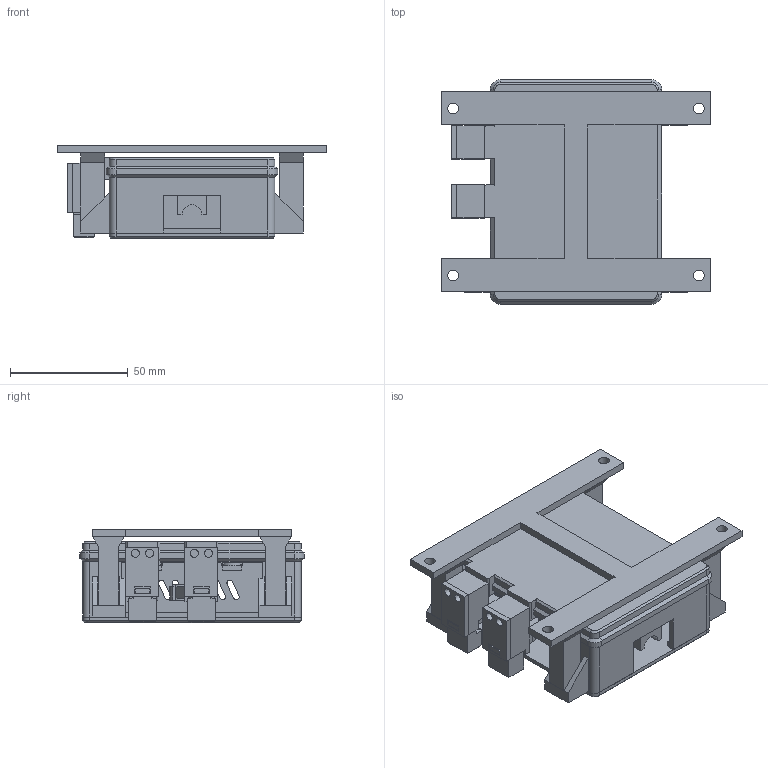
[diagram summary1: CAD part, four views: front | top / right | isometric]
STEP (ISO 10303-21) file: header records copied from the file, then geometry measured from it (millimetres).
FILE_DESCRIPTION(('Open CASCADE Model'),'2;1');
FILE_NAME('Open CASCADE Shape Model','2026-10-19T19:32:54',('Author'),( 'Open CASCADE'),'Open CASCADE STEP processor 7.9','build123d', 'Unknown');
FILE_SCHEMA(('AUTOMOTIVE_DESIGN { 1 0 10303 214 1 1 1 1 }'));
Length unit declared in the file: millimetre
Products named in the file (16): COMPOUND
Assembly tree (15 placements, depth 2):
  COMPOUND
    COMPOUND
    COMPOUND
    COMPOUND
    COMPOUND
    COMPOUND
    COMPOUND
    COMPOUND
    COMPOUND
    COMPOUND
    COMPOUND
    COMPOUND
    COMPOUND
    COMPOUND
    COMPOUND
    COMPOUND
Bounding box: 114.3 x 95.2 x 39.6 mm (x, y, z)
Volume: 94116 mm3; surface area: 74138.1 mm2
Topology: 15 solids, 15 shells, 661 faces, 1698 edges, 1107 vertices
Faces by surface type: plane 522, cylinder 123, cone 16
Full cylindrical faces by diameter (mm): 3.4 x22, 4 x12, 4.1 x6, 4.5 x4
Entity records: 41672 total; most frequent: CARTESIAN_POINT 8452, DIRECTION 5650, LINE 3636, VECTOR 3636, ORIENTED_EDGE 3396, PCURVE 3396, DEFINITIONAL_REPRESENTATION 3396, EDGE_CURVE 1698
One B-rep face of a CAD part: STEP entity #12112.
In plain terms, the planar face has unit normal (0, 1, 0).
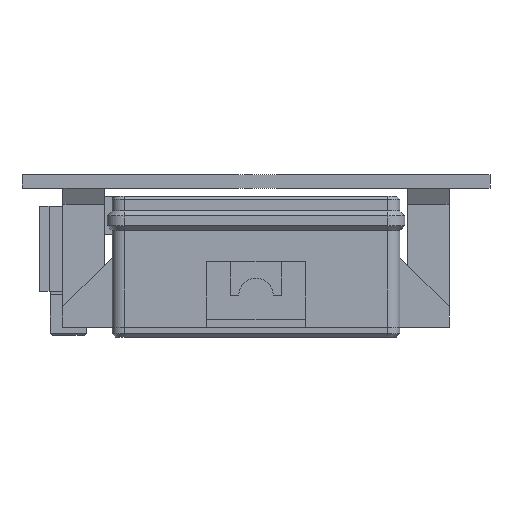
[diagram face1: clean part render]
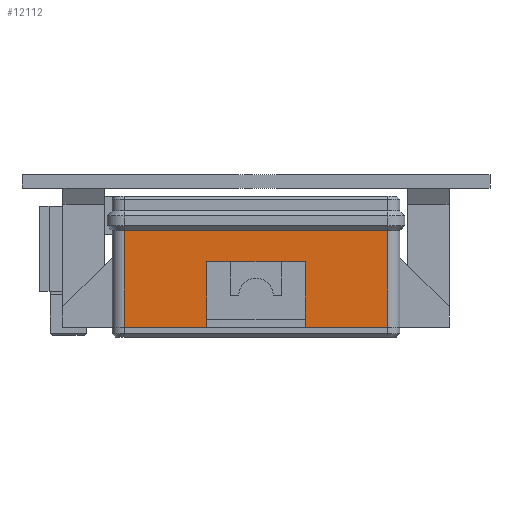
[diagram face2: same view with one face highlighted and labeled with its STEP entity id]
Its self-contained STEP definition (entity closure, numbers rounded to 3 decimals):
#2296 = PLANE('',#2297);
#2297 = AXIS2_PLACEMENT_3D('',#2298,#2299,#2300);
#2298 = CARTESIAN_POINT('',(-35.15,-46.4,32.));
#2299 = DIRECTION('',(0.,0.,1.));
#2300 = DIRECTION('',(1.,0.,-0.));
#5967 = VERTEX_POINT('',#5968);
#5968 = CARTESIAN_POINT('',(32.15,46.4,32.));
#5983 = CYLINDRICAL_SURFACE('',#5984,3.);
#5984 = AXIS2_PLACEMENT_3D('',#5985,#5986,#5987);
#5985 = CARTESIAN_POINT('',(32.15,43.4,0.));
#5986 = DIRECTION('',(0.,0.,1.));
#5987 = DIRECTION('',(1.,0.,-0.));
#5995 = EDGE_CURVE('',#5996,#5967,#5998,.T.);
#5996 = VERTEX_POINT('',#5997);
#5997 = CARTESIAN_POINT('',(12.,46.4,32.));
#5998 = SURFACE_CURVE('',#5999,(#6003,#6010),.PCURVE_S1.);
#5999 = LINE('',#6000,#6001);
#6000 = CARTESIAN_POINT('',(-35.15,46.4,32.));
#6001 = VECTOR('',#6002,1.);
#6002 = DIRECTION('',(1.,0.,-0.));
#6003 = PCURVE('',#2296,#6004);
#6004 = DEFINITIONAL_REPRESENTATION('',(#6005),#6009);
#6005 = LINE('',#6006,#6007);
#6006 = CARTESIAN_POINT('',(0.,92.8));
#6007 = VECTOR('',#6008,1.);
#6008 = DIRECTION('',(1.,0.));
#6009 = ( GEOMETRIC_REPRESENTATION_CONTEXT(2) 
PARAMETRIC_REPRESENTATION_CONTEXT() REPRESENTATION_CONTEXT('2D SPACE',''
  ) );
#6010 = PCURVE('',#6011,#6016);
#6011 = PLANE('',#6012);
#6012 = AXIS2_PLACEMENT_3D('',#6013,#6014,#6015);
#6013 = CARTESIAN_POINT('',(-35.15,46.4,0.));
#6014 = DIRECTION('',(-0.,1.,0.));
#6015 = DIRECTION('',(0.,0.,1.));
#6016 = DEFINITIONAL_REPRESENTATION('',(#6017),#6021);
#6017 = LINE('',#6018,#6019);
#6018 = CARTESIAN_POINT('',(32.,0.));
#6019 = VECTOR('',#6020,1.);
#6020 = DIRECTION('',(0.,1.));
#6021 = ( GEOMETRIC_REPRESENTATION_CONTEXT(2) 
PARAMETRIC_REPRESENTATION_CONTEXT() REPRESENTATION_CONTEXT('2D SPACE',''
  ) );
#6039 = PLANE('',#6040);
#6040 = AXIS2_PLACEMENT_3D('',#6041,#6042,#6043);
#6041 = CARTESIAN_POINT('',(12.,43.5,16.));
#6042 = DIRECTION('',(1.,0.,-0.));
#6043 = DIRECTION('',(0.,0.,1.));
#7090 = PLANE('',#7091);
#7091 = AXIS2_PLACEMENT_3D('',#7092,#7093,#7094);
#7092 = CARTESIAN_POINT('',(-35.15,-46.4,32.));
#7093 = DIRECTION('',(0.,0.,1.));
#7094 = DIRECTION('',(1.,0.,-0.));
#8327 = CYLINDRICAL_SURFACE('',#8328,3.);
#8328 = AXIS2_PLACEMENT_3D('',#8329,#8330,#8331);
#8329 = CARTESIAN_POINT('',(-32.15,43.4,0.));
#8330 = DIRECTION('',(0.,0.,1.));
#8331 = DIRECTION('',(-1.,-0.,0.));
#12063 = VERTEX_POINT('',#12064);
#12064 = CARTESIAN_POINT('',(32.15,46.4,8.4));
#12091 = EDGE_CURVE('',#12063,#5967,#12092,.T.);
#12092 = SURFACE_CURVE('',#12093,(#12097,#12104),.PCURVE_S1.);
#12093 = LINE('',#12094,#12095);
#12094 = CARTESIAN_POINT('',(32.15,46.4,0.));
#12095 = VECTOR('',#12096,1.);
#12096 = DIRECTION('',(0.,0.,1.));
#12097 = PCURVE('',#5983,#12098);
#12098 = DEFINITIONAL_REPRESENTATION('',(#12099),#12103);
#12099 = LINE('',#12100,#12101);
#12100 = CARTESIAN_POINT('',(1.571,0.));
#12101 = VECTOR('',#12102,1.);
#12102 = DIRECTION('',(0.,1.));
#12103 = ( GEOMETRIC_REPRESENTATION_CONTEXT(2) 
PARAMETRIC_REPRESENTATION_CONTEXT() REPRESENTATION_CONTEXT('2D SPACE',''
  ) );
#12104 = PCURVE('',#6011,#12105);
#12105 = DEFINITIONAL_REPRESENTATION('',(#12106),#12110);
#12106 = LINE('',#12107,#12108);
#12107 = CARTESIAN_POINT('',(0.,67.3));
#12108 = VECTOR('',#12109,1.);
#12109 = DIRECTION('',(1.,0.));
#12110 = ( GEOMETRIC_REPRESENTATION_CONTEXT(2) 
PARAMETRIC_REPRESENTATION_CONTEXT() REPRESENTATION_CONTEXT('2D SPACE',''
  ) );
#12112 = ADVANCED_FACE('',(#12113),#6011,.T.);
#12113 = FACE_BOUND('',#12114,.T.);
#12114 = EDGE_LOOP('',(#12115,#12143,#12166,#12189,#12215,#12241,#12260,
    #12261));
#12115 = ORIENTED_EDGE('',*,*,#12116,.F.);
#12116 = EDGE_CURVE('',#12117,#12063,#12119,.T.);
#12117 = VERTEX_POINT('',#12118);
#12118 = CARTESIAN_POINT('',(-32.15,46.4,8.4));
#12119 = SURFACE_CURVE('',#12120,(#12124,#12131),.PCURVE_S1.);
#12120 = LINE('',#12121,#12122);
#12121 = CARTESIAN_POINT('',(-32.15,46.4,8.4));
#12122 = VECTOR('',#12123,1.);
#12123 = DIRECTION('',(1.,0.,-0.));
#12124 = PCURVE('',#6011,#12125);
#12125 = DEFINITIONAL_REPRESENTATION('',(#12126),#12130);
#12126 = LINE('',#12127,#12128);
#12127 = CARTESIAN_POINT('',(8.4,3.));
#12128 = VECTOR('',#12129,1.);
#12129 = DIRECTION('',(0.,1.));
#12130 = ( GEOMETRIC_REPRESENTATION_CONTEXT(2) 
PARAMETRIC_REPRESENTATION_CONTEXT() REPRESENTATION_CONTEXT('2D SPACE',''
  ) );
#12131 = PCURVE('',#12132,#12137);
#12132 = PLANE('',#12133);
#12133 = AXIS2_PLACEMENT_3D('',#12134,#12135,#12136);
#12134 = CARTESIAN_POINT('',(-32.15,47.,7.8));
#12135 = DIRECTION('',(0.,0.707,0.707));
#12136 = DIRECTION('',(-1.,-0.,0.));
#12137 = DEFINITIONAL_REPRESENTATION('',(#12138),#12142);
#12138 = LINE('',#12139,#12140);
#12139 = CARTESIAN_POINT('',(-0.,0.849));
#12140 = VECTOR('',#12141,1.);
#12141 = DIRECTION('',(-1.,0.));
#12142 = ( GEOMETRIC_REPRESENTATION_CONTEXT(2) 
PARAMETRIC_REPRESENTATION_CONTEXT() REPRESENTATION_CONTEXT('2D SPACE',''
  ) );
#12143 = ORIENTED_EDGE('',*,*,#12144,.T.);
#12144 = EDGE_CURVE('',#12117,#12145,#12147,.T.);
#12145 = VERTEX_POINT('',#12146);
#12146 = CARTESIAN_POINT('',(-32.15,46.4,32.));
#12147 = SURFACE_CURVE('',#12148,(#12152,#12159),.PCURVE_S1.);
#12148 = LINE('',#12149,#12150);
#12149 = CARTESIAN_POINT('',(-32.15,46.4,0.));
#12150 = VECTOR('',#12151,1.);
#12151 = DIRECTION('',(0.,0.,1.));
#12152 = PCURVE('',#6011,#12153);
#12153 = DEFINITIONAL_REPRESENTATION('',(#12154),#12158);
#12154 = LINE('',#12155,#12156);
#12155 = CARTESIAN_POINT('',(0.,3.));
#12156 = VECTOR('',#12157,1.);
#12157 = DIRECTION('',(1.,0.));
#12158 = ( GEOMETRIC_REPRESENTATION_CONTEXT(2) 
PARAMETRIC_REPRESENTATION_CONTEXT() REPRESENTATION_CONTEXT('2D SPACE',''
  ) );
#12159 = PCURVE('',#8327,#12160);
#12160 = DEFINITIONAL_REPRESENTATION('',(#12161),#12165);
#12161 = LINE('',#12162,#12163);
#12162 = CARTESIAN_POINT('',(-1.571,0.));
#12163 = VECTOR('',#12164,1.);
#12164 = DIRECTION('',(-0.,1.));
#12165 = ( GEOMETRIC_REPRESENTATION_CONTEXT(2) 
PARAMETRIC_REPRESENTATION_CONTEXT() REPRESENTATION_CONTEXT('2D SPACE',''
  ) );
#12166 = ORIENTED_EDGE('',*,*,#12167,.T.);
#12167 = EDGE_CURVE('',#12145,#12168,#12170,.T.);
#12168 = VERTEX_POINT('',#12169);
#12169 = CARTESIAN_POINT('',(-12.,46.4,32.));
#12170 = SURFACE_CURVE('',#12171,(#12175,#12182),.PCURVE_S1.);
#12171 = LINE('',#12172,#12173);
#12172 = CARTESIAN_POINT('',(-35.15,46.4,32.));
#12173 = VECTOR('',#12174,1.);
#12174 = DIRECTION('',(1.,0.,-0.));
#12175 = PCURVE('',#6011,#12176);
#12176 = DEFINITIONAL_REPRESENTATION('',(#12177),#12181);
#12177 = LINE('',#12178,#12179);
#12178 = CARTESIAN_POINT('',(32.,0.));
#12179 = VECTOR('',#12180,1.);
#12180 = DIRECTION('',(0.,1.));
#12181 = ( GEOMETRIC_REPRESENTATION_CONTEXT(2) 
PARAMETRIC_REPRESENTATION_CONTEXT() REPRESENTATION_CONTEXT('2D SPACE',''
  ) );
#12182 = PCURVE('',#7090,#12183);
#12183 = DEFINITIONAL_REPRESENTATION('',(#12184),#12188);
#12184 = LINE('',#12185,#12186);
#12185 = CARTESIAN_POINT('',(0.,92.8));
#12186 = VECTOR('',#12187,1.);
#12187 = DIRECTION('',(1.,0.));
#12188 = ( GEOMETRIC_REPRESENTATION_CONTEXT(2) 
PARAMETRIC_REPRESENTATION_CONTEXT() REPRESENTATION_CONTEXT('2D SPACE',''
  ) );
#12189 = ORIENTED_EDGE('',*,*,#12190,.T.);
#12190 = EDGE_CURVE('',#12168,#12191,#12193,.T.);
#12191 = VERTEX_POINT('',#12192);
#12192 = CARTESIAN_POINT('',(-12.,46.4,16.));
#12193 = SURFACE_CURVE('',#12194,(#12198,#12204),.PCURVE_S1.);
#12194 = LINE('',#12195,#12196);
#12195 = CARTESIAN_POINT('',(-12.,46.4,8.));
#12196 = VECTOR('',#12197,1.);
#12197 = DIRECTION('',(-0.,0.,-1.));
#12198 = PCURVE('',#6011,#12199);
#12199 = DEFINITIONAL_REPRESENTATION('',(#12200),#12203);
#12200 = B_SPLINE_CURVE_WITH_KNOTS('',1,(#12201,#12202),.UNSPECIFIED.,
  .F.,.F.,(2,2),(-24.,-8.),.PIECEWISE_BEZIER_KNOTS.);
#12201 = CARTESIAN_POINT('',(32.,23.15));
#12202 = CARTESIAN_POINT('',(16.,23.15));
#12203 = ( GEOMETRIC_REPRESENTATION_CONTEXT(2) 
PARAMETRIC_REPRESENTATION_CONTEXT() REPRESENTATION_CONTEXT('2D SPACE',''
  ) );
#12204 = PCURVE('',#12205,#12210);
#12205 = PLANE('',#12206);
#12206 = AXIS2_PLACEMENT_3D('',#12207,#12208,#12209);
#12207 = CARTESIAN_POINT('',(-12.,43.5,16.));
#12208 = DIRECTION('',(1.,0.,-0.));
#12209 = DIRECTION('',(0.,0.,1.));
#12210 = DEFINITIONAL_REPRESENTATION('',(#12211),#12214);
#12211 = B_SPLINE_CURVE_WITH_KNOTS('',1,(#12212,#12213),.UNSPECIFIED.,
  .F.,.F.,(2,2),(-24.,-8.),.PIECEWISE_BEZIER_KNOTS.);
#12212 = CARTESIAN_POINT('',(16.,-2.9));
#12213 = CARTESIAN_POINT('',(0.,-2.9));
#12214 = ( GEOMETRIC_REPRESENTATION_CONTEXT(2) 
PARAMETRIC_REPRESENTATION_CONTEXT() REPRESENTATION_CONTEXT('2D SPACE',''
  ) );
#12215 = ORIENTED_EDGE('',*,*,#12216,.T.);
#12216 = EDGE_CURVE('',#12191,#12217,#12219,.T.);
#12217 = VERTEX_POINT('',#12218);
#12218 = CARTESIAN_POINT('',(12.,46.4,16.));
#12219 = SURFACE_CURVE('',#12220,(#12224,#12230),.PCURVE_S1.);
#12220 = LINE('',#12221,#12222);
#12221 = CARTESIAN_POINT('',(-23.575,46.4,16.));
#12222 = VECTOR('',#12223,1.);
#12223 = DIRECTION('',(1.,0.,-0.));
#12224 = PCURVE('',#6011,#12225);
#12225 = DEFINITIONAL_REPRESENTATION('',(#12226),#12229);
#12226 = B_SPLINE_CURVE_WITH_KNOTS('',1,(#12227,#12228),.UNSPECIFIED.,
  .F.,.F.,(2,2),(11.575,35.575),.PIECEWISE_BEZIER_KNOTS.);
#12227 = CARTESIAN_POINT('',(16.,23.15));
#12228 = CARTESIAN_POINT('',(16.,47.15));
#12229 = ( GEOMETRIC_REPRESENTATION_CONTEXT(2) 
PARAMETRIC_REPRESENTATION_CONTEXT() REPRESENTATION_CONTEXT('2D SPACE',''
  ) );
#12230 = PCURVE('',#12231,#12236);
#12231 = PLANE('',#12232);
#12232 = AXIS2_PLACEMENT_3D('',#12233,#12234,#12235);
#12233 = CARTESIAN_POINT('',(-12.,43.5,16.));
#12234 = DIRECTION('',(0.,0.,1.));
#12235 = DIRECTION('',(1.,0.,-0.));
#12236 = DEFINITIONAL_REPRESENTATION('',(#12237),#12240);
#12237 = B_SPLINE_CURVE_WITH_KNOTS('',1,(#12238,#12239),.UNSPECIFIED.,
  .F.,.F.,(2,2),(11.575,35.575),.PIECEWISE_BEZIER_KNOTS.);
#12238 = CARTESIAN_POINT('',(0.,2.9));
#12239 = CARTESIAN_POINT('',(24.,2.9));
#12240 = ( GEOMETRIC_REPRESENTATION_CONTEXT(2) 
PARAMETRIC_REPRESENTATION_CONTEXT() REPRESENTATION_CONTEXT('2D SPACE',''
  ) );
#12241 = ORIENTED_EDGE('',*,*,#12242,.F.);
#12242 = EDGE_CURVE('',#5996,#12217,#12243,.T.);
#12243 = SURFACE_CURVE('',#12244,(#12248,#12254),.PCURVE_S1.);
#12244 = LINE('',#12245,#12246);
#12245 = CARTESIAN_POINT('',(12.,46.4,8.));
#12246 = VECTOR('',#12247,1.);
#12247 = DIRECTION('',(-0.,0.,-1.));
#12248 = PCURVE('',#6011,#12249);
#12249 = DEFINITIONAL_REPRESENTATION('',(#12250),#12253);
#12250 = B_SPLINE_CURVE_WITH_KNOTS('',1,(#12251,#12252),.UNSPECIFIED.,
  .F.,.F.,(2,2),(-24.,-8.),.PIECEWISE_BEZIER_KNOTS.);
#12251 = CARTESIAN_POINT('',(32.,47.15));
#12252 = CARTESIAN_POINT('',(16.,47.15));
#12253 = ( GEOMETRIC_REPRESENTATION_CONTEXT(2) 
PARAMETRIC_REPRESENTATION_CONTEXT() REPRESENTATION_CONTEXT('2D SPACE',''
  ) );
#12254 = PCURVE('',#6039,#12255);
#12255 = DEFINITIONAL_REPRESENTATION('',(#12256),#12259);
#12256 = B_SPLINE_CURVE_WITH_KNOTS('',1,(#12257,#12258),.UNSPECIFIED.,
  .F.,.F.,(2,2),(-24.,-8.),.PIECEWISE_BEZIER_KNOTS.);
#12257 = CARTESIAN_POINT('',(16.,-2.9));
#12258 = CARTESIAN_POINT('',(0.,-2.9));
#12259 = ( GEOMETRIC_REPRESENTATION_CONTEXT(2) 
PARAMETRIC_REPRESENTATION_CONTEXT() REPRESENTATION_CONTEXT('2D SPACE',''
  ) );
#12260 = ORIENTED_EDGE('',*,*,#5995,.T.);
#12261 = ORIENTED_EDGE('',*,*,#12091,.F.);
